VERSION 5.8 ;
BUSBITCHARS "[]" ;
DIVIDERCHAR "/" ;

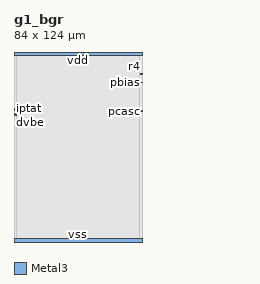
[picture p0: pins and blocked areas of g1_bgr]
MACRO g1_bgr
  CLASS BLOCK ;
  ORIGIN 0 0 ;
  FOREIGN g1_bgr 0 0 ;
  SIZE 84 BY 124 ;
  SYMMETRY X Y ;
  PIN vdd
    DIRECTION INOUT ;
    USE POWER ;
    PORT
      LAYER Metal3 ;
        RECT 0 122 84 124 ;
    END
  END vdd
  PIN vss
    DIRECTION INOUT ;
    USE GROUND ;
    PORT
      LAYER Metal3 ;
        RECT 0 0 84 2 ;
    END
  END vss
  PIN r4
    DIRECTION INPUT ;
    USE SIGNAL ;
    PORT
      LAYER Metal3 ;
        RECT 82.5 109.45 84 109.75 ;
    END
  END r4
  PIN vref
    DIRECTION OUTPUT ;
    USE SIGNAL ;
    PORT
      LAYER Metal3 ;
        RECT 0 85.85 1.5 86.15 ;
    END
  END vref
  PIN iptat
    DIRECTION OUTPUT ;
    USE SIGNAL ;
    PORT
      LAYER Metal3 ;
        RECT 0 87.05 1.5 87.35 ;
    END
  END iptat
  PIN pbias
    DIRECTION OUTPUT ;
    USE SIGNAL ;
    PORT
      LAYER Metal3 ;
        RECT 82.5 104.05 84 104.35 ;
    END
  END pbias
  PIN pcasc
    DIRECTION OUTPUT ;
    USE SIGNAL ;
    PORT
      LAYER Metal3 ;
        RECT 82.5 85.25 84 85.55 ;
    END
  END pcasc
  PIN vbe
    DIRECTION OUTPUT ;
    USE SIGNAL ;
    PORT
      LAYER Metal3 ;
        RECT 0 83.45 1.5 83.75 ;
    END
  END vbe
  PIN dvbe
    DIRECTION OUTPUT ;
    USE SIGNAL ;
    PORT
      LAYER Metal3 ;
        RECT 0 82.85 1.5 83.15 ;
    END
  END dvbe
  OBS
    LAYER Metal1 ;
      RECT 0 0 84 124 ;
    LAYER Metal2 ;
      RECT 0 0 84 124 ;
    LAYER Metal3 ;
      RECT 1.8 2.6 82 121.4 ;
  END
END g1_bgr

END LIBRARY
